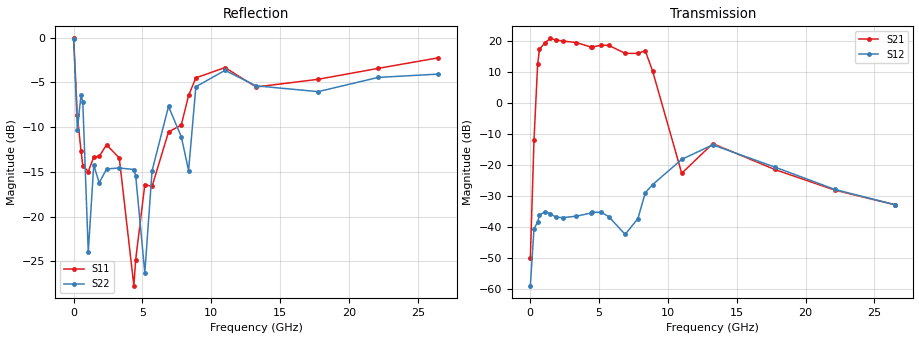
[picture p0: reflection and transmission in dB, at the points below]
!Agilent Technologies,N5242A,MY52422126,A.09.90.01
!Agilent N5242A: A.09.90.01
!Date: Wednesday, November 18, 2015 20:52:49
!Correction: S11(Full 2 Port(1,2))
!S21(Full 2 Port(1,2))
!S12(Full 2 Port(1,2))
!S22(Full 2 Port(1,2))
!S2P File: Measurements: S11, S21, S12, S22:
# Hz S  dB  R 50
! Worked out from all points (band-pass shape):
!   201 points, 10 MHz to 26.5 GHz, reference 50 ohm
!   highest |S21| = 21.01 dB at 1.467 GHz (marker M1); lowest = -50.1 dB at 10 MHz (marker M2)
!   |S21| within 3 dB of the highest: 719.7 MHz to 6.066 GHz (5.346 GHz wide, 158 % of centre)
!   lowest |S11| = -27.7 dB at 4.381 GHz (marker M3), VSWR 1.09, Z = 52.5 - j3.43 ohm
!   |S11| at or under -10 dB: 333.3 MHz to 7.143 GHz (6.81 GHz wide, 182 % of centre)
!   |S22| runs from -30.9 to -0.1 dB; largest |S21 - S12| = 11
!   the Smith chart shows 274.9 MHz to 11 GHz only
!   S11 on the Smith chart (normalised r, x): 274.9 MHz: 0.50, -0.26; 672.2 MHz: 1.11, +0.40; 3.321 GHz: 1.06, -0.44; 6.897 GHz: 1.30, -0.64; 8.884 GHz: 0.44, -0.81; 11 GHz: 0.20, -0.26
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1e7  -0.09 -7.0  -50.11 -129.6  -59.00 51.0  -0.13 -6.2
2.749e8  -8.67 -142.2  -11.93 -110.5  -40.61 -66.4  -10.30 -157.7
5.398e8  -12.62 107.2  12.62 168.8  -38.40 176.5  -6.45 20.6
6.7225e8  -14.29 64.3  17.51 113.7  -36.16 120.4  -7.21 -33.3
1.0696e9  -14.96 42.3  19.59 15.1  -35.12 28.6  -23.96 3.6
1.46695e9  -13.35 9.8  21.01 -45.2  -35.68 -23.7  -14.23 -22.1
1.8643e9  -13.28 -1.0  20.49 -95.6  -36.87 -52.4  -16.23 -24.2
2.3941e9  -11.97 -23.4  20.13 -148.7  -36.95 -86.4  -14.68 -31.1
3.32125e9  -13.45 -70.5  19.67 125.1  -36.54 -147.4  -14.56 -49.8
4.38085e9  -27.71 -52.4  18.26 35.3  -35.53 139.1  -14.74 -78.3
4.5133e9  -24.80 -22.7  18.22 25.5  -35.25 130.5  -15.43 -85.6
5.17555e9  -16.43 -34.7  18.82 -30.5  -35.28 84.5  -26.28 -60.8
5.70535e9  -16.61 -44.1  18.74 -82.4  -36.68 51.5  -14.86 -14.4
6.8974e9  -10.54 -49.6  16.16 166.1  -42.42 21.4  -7.69 -75.6
7.82455e9  -9.77 -67.4  16.16 79.6  -37.28 84.8  -11.07 -133.2
8.35435e9  -6.47 -64.2  17.05 1.7  -28.95 58.4  -14.85 -6.1
8.88415e9  -4.50 -95.0  10.49 -90.2  -26.33 25.4  -5.49 -75.0
1.100335e10  -3.35 -149.9  -22.64 -102.4  -18.14 -81.5  -3.66 -144.8
1.3255e10  -5.52 149.3  -13.04 164.9  -13.43 170.5  -5.39 154.4
1.77583e10  -4.66 47.0  -21.41 -62.9  -20.62 -60.2  -6.04 48.7
2.212915e10  -3.44 -84.9  -28.10 156.8  -27.87 154.8  -4.45 -88.5
2.65e10  -2.26 -161.5  -32.84 47.1  -32.80 43.0  -4.08 -145.8
